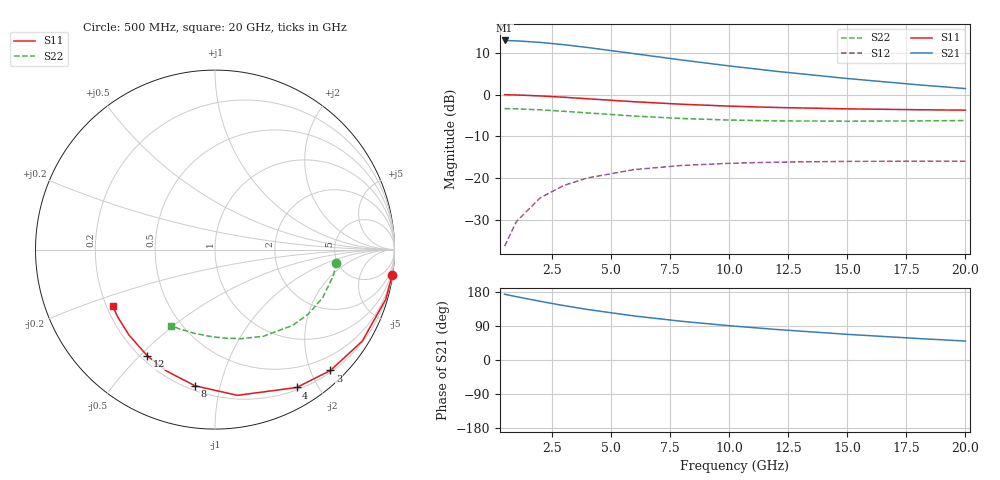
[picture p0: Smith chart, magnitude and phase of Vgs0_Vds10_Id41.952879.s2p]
# Hz S RI R 50
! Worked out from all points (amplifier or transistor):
!   12 points, 500 MHz to 20 GHz, reference 50 ohm
!   highest |S21| = 13.0 dB at 500 MHz (marker M1)
!   |S21| within 3 dB of that: start of sweep to 5.759 GHz
!   unconditionally stable (mu >= 1): 19.46 GHz to end of sweep
!   at 2 GHz: K = 0.10, MSG = 18.7 dB, |S12| = -24.8 dB
!   at 8 GHz: K = 0.39, MSG = 12.7 dB, |S12| = -17.0 dB
!   at 20 GHz: K = 1.03, MAG = 7.6 dB, |S12| = -16.0 dB
!   S11 on the Smith chart (normalised r, x): 500 MHz: 0, -14; 3 GHz: 0.23, -2.32; 4 GHz: 0.23, -1.73; 8 GHz: 0.23, -0.84; 12 GHz: 0.23, -0.53; 20 GHz: 0.22, -0.25
5e8  0.9875 -0.1418  -4.441 0.5008  0.00147 0.0151  0.6765 -0.0731
1e9  0.9512 -0.2774  -4.311 0.979  0.00574 0.0295  0.6601 -0.1434
2e9  0.8205 -0.5098  -3.84 1.795  0.0211 0.0537  0.6004 -0.267
3e9  0.6434 -0.6733  -3.204 2.36  0.0418 0.0696  0.5189 -0.3601
4e9  0.4549 -0.7683  -2.529 2.677  0.0636 0.0773  0.4309 -0.4229
6e9  0.1247 -0.812  -1.361 2.784  0.1012 0.0757  0.2707 -0.4825
8e9  -0.1114 -0.7588  -0.5448 2.546  0.1267 0.0628  0.146 -0.4965
1e10  -0.2703 -0.6764  -0.0192 2.212  0.1424 0.047  0.0507 -0.4932
1.2e10  -0.3776 -0.5913  0.3127 1.88  0.1516 0.0316  -0.0255 -0.4839
1.5e10  -0.4802 -0.475  0.5916 1.445  0.1578 0.0111  -0.1189 -0.4653
1.8e10  -0.542 -0.375  0.7214 1.097  0.159 -0.006  -0.1968 -0.4424
2e10  -0.5696 -0.3162  0.7609 0.906  0.1583 -0.0157  -0.2428 -0.4246
